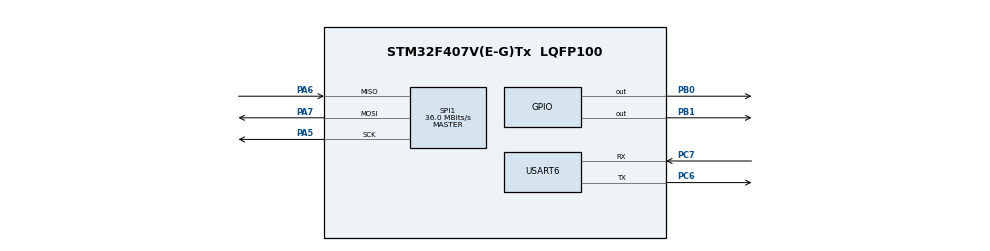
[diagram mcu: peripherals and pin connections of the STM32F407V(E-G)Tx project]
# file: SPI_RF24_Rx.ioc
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Mcu.Family=STM32F4
Mcu.Name=STM32F407V(E-G)Tx
Mcu.Package=LQFP100
NVIC.PriorityGroup=NVIC_PRIORITYGROUP_4
PA13.Mode=Serial_Wire
PA13.Signal=SYS_JTMS-SWDIO
PA14.Mode=Serial_Wire
PA14.Signal=SYS_JTCK-SWCLK
PA5.Mode=Full_Duplex_Master
PA5.Signal=SPI1_SCK
PA6.Mode=Full_Duplex_Master
PA6.Signal=SPI1_MISO
PA7.Mode=Full_Duplex_Master
PA7.Signal=SPI1_MOSI
PB0.Signal=GPIO_Output
PB1.Signal=GPIO_Output
PC6.Mode=Asynchronous
PC6.Signal=USART6_TX
PC7.Mode=Asynchronous
PC7.Signal=USART6_RX
PH0-OSC_IN.Mode=HSE-External-Clock-Source
PH0-OSC_IN.Signal=RCC_OSC_IN
PH1-OSC_OUT.Mode=HSE-External-Clock-Source
PH1-OSC_OUT.Signal=RCC_OSC_OUT
ProjectManager.HeapSize=0x200
ProjectManager.StackSize=0x400
ProjectManager.TargetToolchain=STM32CubeIDE
RCC.48MHZClocksFreq_Value=36000000
RCC.AHBFreq_Value=72000000
RCC.APB1CLKDivider=RCC_HCLK_DIV2
RCC.APB1Freq_Value=36000000
RCC.APB1TimFreq_Value=72000000
RCC.APB2Freq_Value=72000000
RCC.APB2TimFreq_Value=72000000
RCC.CortexFreq_Value=72000000
RCC.HCLKFreq_Value=72000000
RCC.HSE_VALUE=25000000
RCC.HSI_VALUE=16000000
RCC.LSE_VALUE=32768
RCC.PLLM=8
RCC.PLLN=72
RCC.SYSCLKFreq_VALUE=72000000
RCC.SYSCLKSource=RCC_SYSCLKSOURCE_PLLCLK
RCC.VCOOutputFreq_Value=144000000
SPI1.CalculateBaudRate=36.0 MBits/s
SPI1.Direction=SPI_DIRECTION_2LINES
SPI1.Mode=SPI_MODE_MASTER
SPI1.VirtualType=VM_MASTER
USART6.VirtualMode=VM_ASYNC
board=custom

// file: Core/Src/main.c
/* USER CODE BEGIN Header */
/**
 ******************************************************************************
 * @file           : main.c
 * @brief          : Main program body
 ******************************************************************************
 * @attention
 *
 * Copyright (c) 2023 STMicroelectronics.
 * All rights reserved.
 *
 * This software is licensed under terms that can be found in the LICENSE file
 * in the root directory of this software component.
 * If no LICENSE file comes with this software, it is provided AS-IS.
 *
 ******************************************************************************
 */
/* USER CODE END Header */
#include "main.h"

/* USER CODE BEGIN Includes */
#include "MY_NRF24.h"
#include <stdio.h>
/* USER CODE END Includes */

/* USER CODE BEGIN PD */
#define nrf_CSN_PORT		GPIOB
#define nrf_CSN_PIN			GPIO_PIN_0

#define nrf_CE_PORT			GPIOB
#define nrf_CE_PIN			GPIO_PIN_1
/* USER CODE END PD */

SPI_HandleTypeDef hspi1;

UART_HandleTypeDef huart6;

/* USER CODE BEGIN PV */
uint64_t TxpipeAddrs = 0xAABBCCDDEE;
uint64_t RxpipeAddrs = 0xAABBCCDDEE;
char myTxData[32] = "Hello World!";
char myRxData[50];
char AckPayload[32];
/* USER CODE END PV */

void SystemClock_Config(void);
static void MX_GPIO_Init(void);
static void MX_SPI1_Init(void);
static void MX_USART6_UART_Init(void);

int main(void) {

	/* MCU Configuration--------------------------------------------------------*/

	/* Reset of all peripherals, Initializes the Flash interface and the Systick. */
	HAL_Init();

	/* Configure the system clock */
	SystemClock_Config();

	/* Initialize all configured peripherals */
	MX_GPIO_Init();
	MX_SPI1_Init();
	MX_USART6_UART_Init();
	/* USER CODE BEGIN 2 */
	char a[80] = "----------------Tx---------------------\r\n";
	HAL_UART_Transmit(&huart6, (uint8_t*) a, strlen(a), 10);

	NRF24_begin(GPIOB, nrf_CSN_PIN, nrf_CE_PIN, hspi1);
	nrf24_DebugUART_Init(huart6);

	uint8_t reg8Val;
	reg8Val = NRF24_read_register(0x00);
	sprintf(a, "REG0:		%02X\r\n", reg8Val);
	HAL_UART_Transmit(&huart6, (uint8_t*) a, strlen(a), 10);
	reg8Val = NRF24_read_register(0x01);
	sprintf(a, "REG1:		%02X\r\n", reg8Val);
	HAL_UART_Transmit(&huart6, (uint8_t*) a, strlen(a), 10);
	reg8Val = NRF24_read_register(0x02);
	sprintf(a, "REG2:		%02X\r\n", reg8Val);
	HAL_UART_Transmit(&huart6, (uint8_t*) a, strlen(a), 10);
	reg8Val = NRF24_read_register(0x03);
	sprintf(a, "REG3:		%02X\r\n", reg8Val);
	HAL_UART_Transmit(&huart6, (uint8_t*) a, strlen(a), 10);
	reg8Val = NRF24_read_register(0x04);
	sprintf(a, "REG4:		%02X\r\n", reg8Val);
	HAL_UART_Transmit(&huart6, (uint8_t*) a, strlen(a), 10);
	reg8Val = NRF24_read_register(0x05);
	sprintf(a, "REG5:		%02X\r\n", reg8Val);
	HAL_UART_Transmit(&huart6, (uint8_t*) a, strlen(a), 10);
	reg8Val = NRF24_read_register(0x06);
	sprintf(a, "REG6:		%02X\r\n", reg8Val);
	HAL_UART_Transmit(&huart6, (uint8_t*) a, strlen(a), 10);
	reg8Val = NRF24_read_register(0x07);
	sprintf(a, "REG7:		%02X\r\n", reg8Val);
	HAL_UART_Transmit(&huart6, (uint8_t*) a, strlen(a), 10);
	reg8Val = NRF24_read_register(0x08);
	sprintf(a, "REG8:		%02X\r\n", reg8Val);
	HAL_UART_Transmit(&huart6, (uint8_t*) a, strlen(a), 10);
	reg8Val = NRF24_read_register(0x09);
	sprintf(a, "REG9:		%02X\r\n", reg8Val);
	HAL_UART_Transmit(&huart6, (uint8_t*) a, strlen(a), 10);
	printRadioSettings();

	NRF24_stopListening();

	NRF24_openReadingPipe(1, RxpipeAddrs);

	NRF24_setAutoAck(false);

	NRF24_startListening();
	/* USER CODE END 2 */

	/* Infinite loop */
	/* USER CODE BEGIN WHILE */
	while (1) {
		if(NRF24_available())
		{
			NRF24_read(myRxData, 32);

			myRxData[32] = '\r'; myRxData[32+1] = '\n';
			HAL_UART_Transmit(&huart6, (uint8_t *)myRxData, 32+2, 10);
		}
		HAL_Delay(1000);
		/* USER CODE END WHILE */

	}
}

void SystemClock_Config(void) {
	RCC_OscInitTypeDef RCC_OscInitStruct = { 0 };
	RCC_ClkInitTypeDef RCC_ClkInitStruct = { 0 };

	/** Configure the main internal regulator output voltage
	 */
	__HAL_RCC_PWR_CLK_ENABLE();
	__HAL_PWR_VOLTAGESCALING_CONFIG(PWR_REGULATOR_VOLTAGE_SCALE1);

	/** Initializes the RCC Oscillators according to the specified parameters
	 * in the RCC_OscInitTypeDef structure.
	 */
	RCC_OscInitStruct.OscillatorType = RCC_OSCILLATORTYPE_HSI;
	RCC_OscInitStruct.HSIState = RCC_HSI_ON;
	RCC_OscInitStruct.HSICalibrationValue = RCC_HSICALIBRATION_DEFAULT;
	RCC_OscInitStruct.PLL.PLLState = RCC_PLL_NONE;
	if (HAL_RCC_OscConfig(&RCC_OscInitStruct) != HAL_OK) {
		Error_Handler();
	}

	/** Initializes the CPU, AHB and APB buses clocks
	 */
	RCC_ClkInitStruct.ClockType = RCC_CLOCKTYPE_HCLK | RCC_CLOCKTYPE_SYSCLK
			| RCC_CLOCKTYPE_PCLK1 | RCC_CLOCKTYPE_PCLK2;
	RCC_ClkInitStruct.SYSCLKSource = RCC_SYSCLKSOURCE_HSI;
	RCC_ClkInitStruct.AHBCLKDivider = RCC_SYSCLK_DIV1;
	RCC_ClkInitStruct.APB1CLKDivider = RCC_HCLK_DIV1;
	RCC_ClkInitStruct.APB2CLKDivider = RCC_HCLK_DIV1;

	if (HAL_RCC_ClockConfig(&RCC_ClkInitStruct, FLASH_LATENCY_0) != HAL_OK) {
		Error_Handler();
	}
}

static void MX_SPI1_Init(void) {

	/* SPI1 parameter configuration*/
	hspi1.Instance = SPI1;
	hspi1.Init.Mode = SPI_MODE_MASTER;
	hspi1.Init.Direction = SPI_DIRECTION_2LINES;
	hspi1.Init.DataSize = SPI_DATASIZE_8BIT;
	hspi1.Init.CLKPolarity = SPI_POLARITY_LOW;
	hspi1.Init.CLKPhase = SPI_PHASE_1EDGE;
	hspi1.Init.NSS = SPI_NSS_SOFT;
	hspi1.Init.BaudRatePrescaler = SPI_BAUDRATEPRESCALER_2;
	hspi1.Init.FirstBit = SPI_FIRSTBIT_MSB;
	hspi1.Init.TIMode = SPI_TIMODE_DISABLE;
	hspi1.Init.CRCCalculation = SPI_CRCCALCULATION_DISABLE;
	hspi1.Init.CRCPolynomial = 10;
	if (HAL_SPI_Init(&hspi1) != HAL_OK) {
		Error_Handler();
	}

}

static void MX_USART6_UART_Init(void) {

	huart6.Instance = USART6;
	huart6.Init.BaudRate = 115200;
	huart6.Init.WordLength = UART_WORDLENGTH_8B;
	huart6.Init.StopBits = UART_STOPBITS_1;
	huart6.Init.Parity = UART_PARITY_NONE;
	huart6.Init.Mode = UART_MODE_TX_RX;
	huart6.Init.HwFlowCtl = UART_HWCONTROL_NONE;
	huart6.Init.OverSampling = UART_OVERSAMPLING_16;
	if (HAL_UART_Init(&huart6) != HAL_OK) {
		Error_Handler();
	}

}

static void MX_GPIO_Init(void) {
	GPIO_InitTypeDef GPIO_InitStruct = { 0 };

	/* GPIO Ports Clock Enable */
	__HAL_RCC_GPIOA_CLK_ENABLE();
	__HAL_RCC_GPIOB_CLK_ENABLE();
	__HAL_RCC_GPIOC_CLK_ENABLE();

	/*Configure GPIO pin Output Level */
	HAL_GPIO_WritePin(GPIOB, GPIO_PIN_0 | GPIO_PIN_1, GPIO_PIN_RESET);

	/*Configure GPIO pins : PB0 PB1 */
	GPIO_InitStruct.Pin = GPIO_PIN_0 | GPIO_PIN_1;
	GPIO_InitStruct.Mode = GPIO_MODE_OUTPUT_PP;
	GPIO_InitStruct.Pull = GPIO_NOPULL;
	GPIO_InitStruct.Speed = GPIO_SPEED_FREQ_LOW;
	HAL_GPIO_Init(GPIOB, &GPIO_InitStruct);

}

void Error_Handler(void) {
	__disable_irq();
	while (1) {
	}
}
